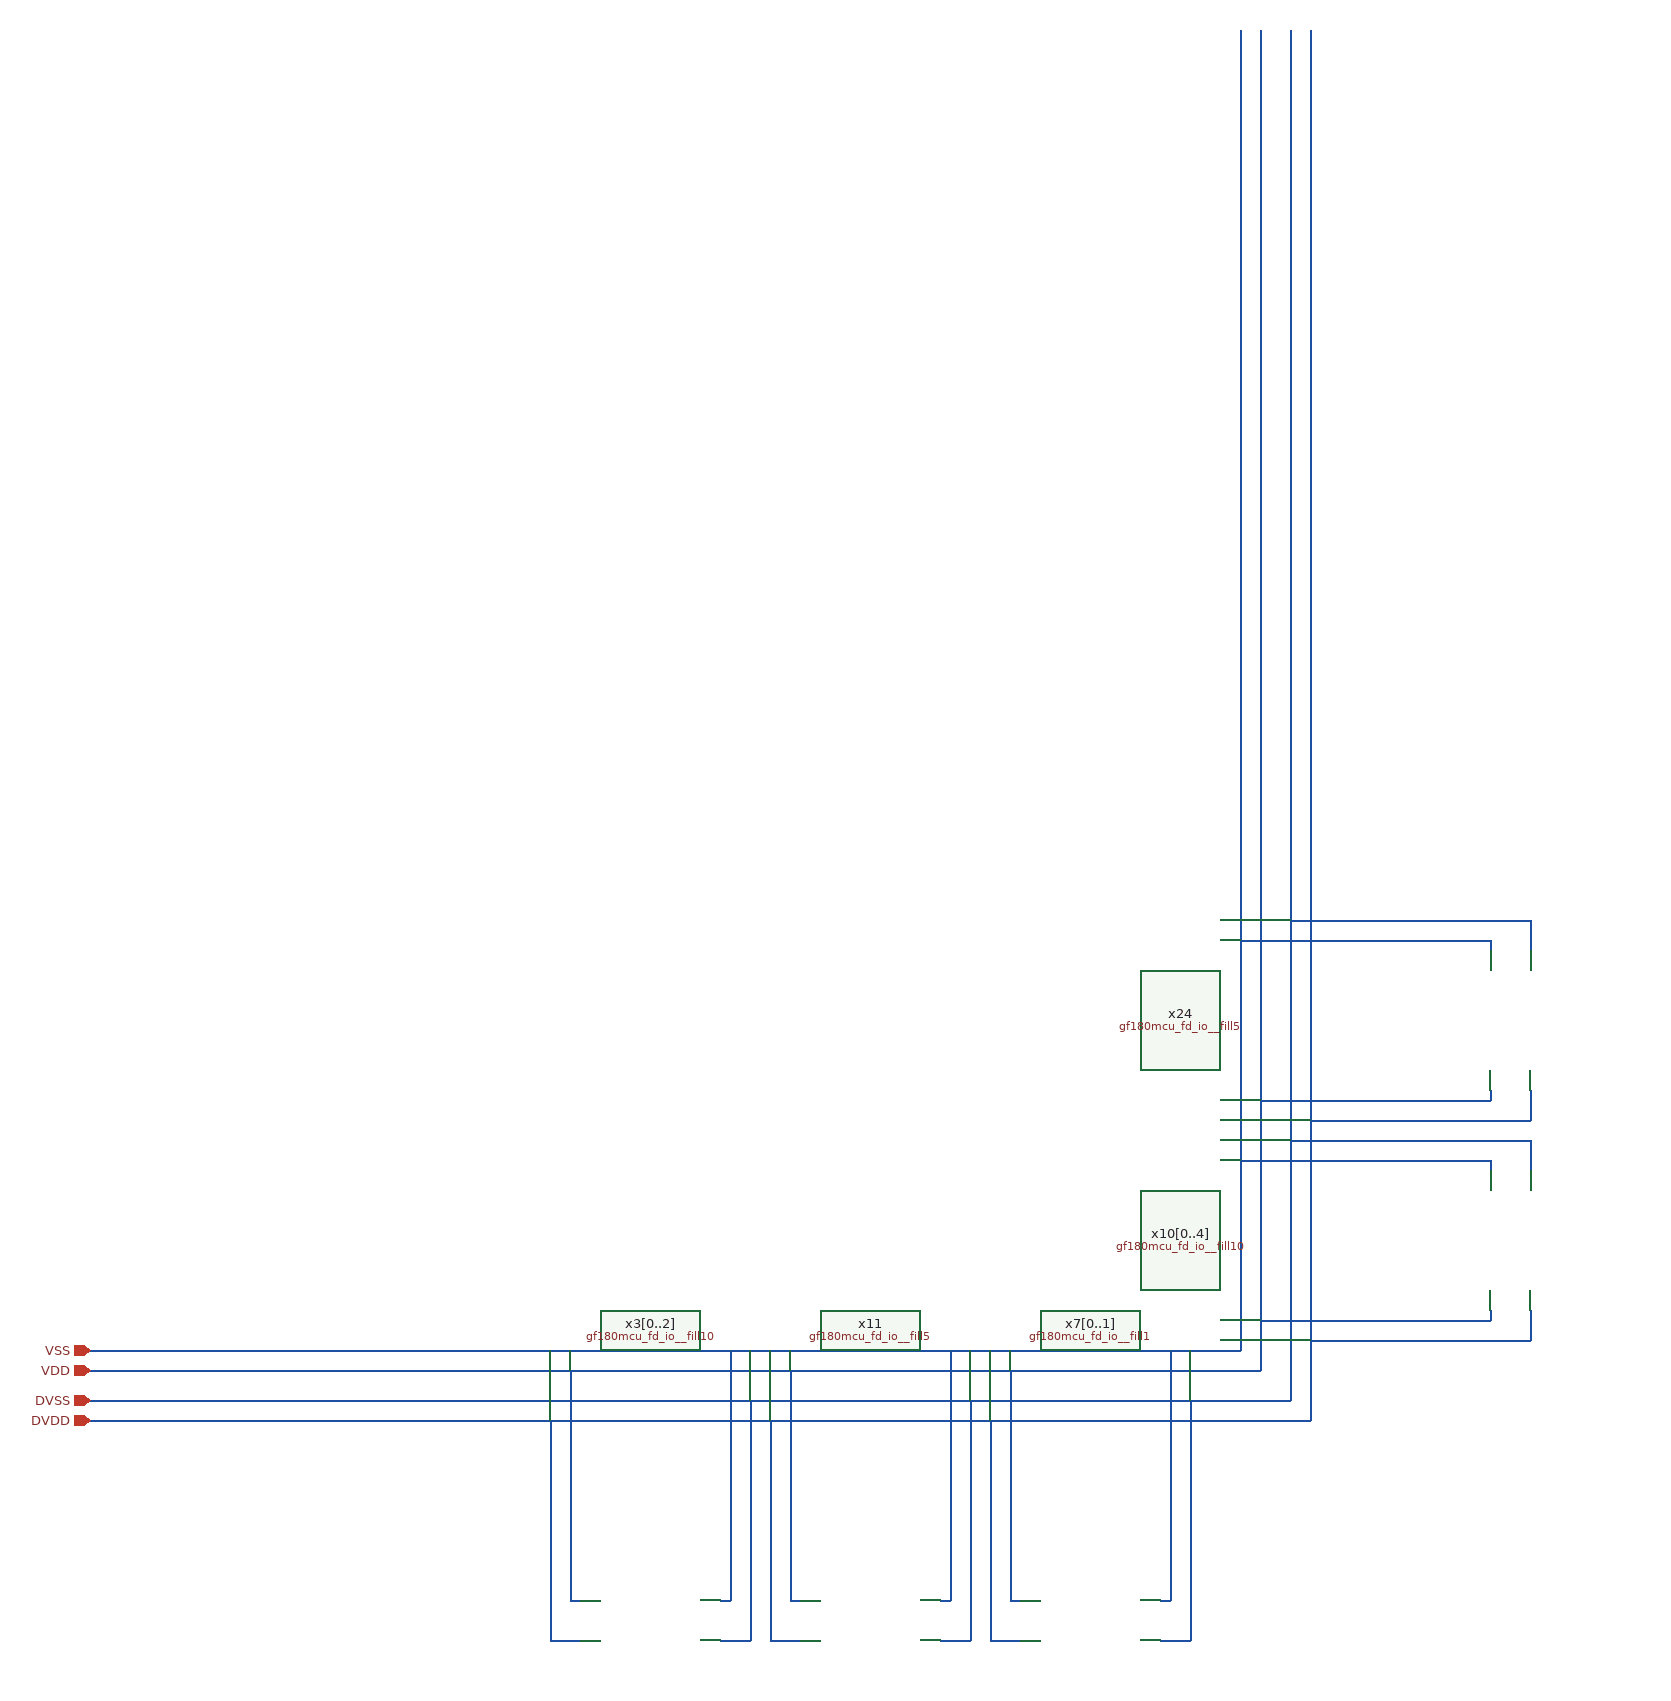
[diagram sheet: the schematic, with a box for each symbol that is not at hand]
v {xschem version=3.4.8RC file_version=1.3}
G {}
K {}
V {}
S {}
F {}
E {}
N 1210 220 1230 220 {lab=DVDD}
N 1200 0 1200 220 {lab=DVDD}
N 1220 180 1230 180 {lab=VDD}
N 1200 220 1210 220 {lab=DVDD}
N 1220 -50 1220 180 {lab=VDD}
N 1370 220 1400 220 {lab=DVSS}
N 1400 -20 1400 220 {lab=DVSS}
N 1370 180 1380 180 {lab=VSS}
N 1380 -70 1380 180 {lab=VSS}
N 740 0 1210 0 {lab=DVDD}
N 1210 0 1830 0 {lab=DVDD}
N 740 -20 1830 -20 {lab=DVSS}
N 740 -50 1860 -50 {lab=VDD}
N 740 -70 1860 -70 {lab=VSS}
N 1430 220 1450 220 {lab=DVDD}
N 1420 0 1420 220 {lab=DVDD}
N 1440 180 1450 180 {lab=VDD}
N 1420 220 1430 220 {lab=DVDD}
N 1440 -50 1440 180 {lab=VDD}
N 1590 220 1620 220 {lab=DVSS}
N 1620 -20 1620 220 {lab=DVSS}
N 1590 180 1600 180 {lab=VSS}
N 1600 -70 1600 180 {lab=VSS}
N 1650 220 1670 220 {lab=DVDD}
N 1640 0 1640 220 {lab=DVDD}
N 1660 180 1670 180 {lab=VDD}
N 1640 220 1650 220 {lab=DVDD}
N 1660 -50 1660 180 {lab=VDD}
N 1810 220 1840 220 {lab=DVSS}
N 1840 -20 1840 220 {lab=DVSS}
N 1810 180 1820 180 {lab=VSS}
N 1820 -70 1820 180 {lab=VSS}
N 1830 -20 1870 -20 {lab=DVSS}
N 1830 -0 1870 -0 {lab=DVDD}
N 1860 -50 1870 -50 {lab=VDD}
N 1860 -70 1870 -70 {lab=VSS}
N 1890 -1390 1890 -70 {lab=VSS}
N 1910 -1390 1910 -70 {lab=VDD}
N 1940 -1390 1940 -70 {lab=DVSS}
N 1960 -1390 1960 -70 {lab=DVDD}
N 1880 -70 1890 -70 {lab=VSS}
N 1880 -50 1910 -50 {lab=VDD}
N 1910 -70 1910 -50 {lab=VDD}
N 1880 -20 1940 -20 {lab=DVSS}
N 1940 -70 1940 -20 {lab=DVSS}
N 1880 0 1960 0 {lab=DVDD}
N 1960 -70 1960 0 {lab=DVDD}
N 2180 -110 2180 -90 {lab=DVDD}
N 1960 -80 2180 -80 {lab=DVDD}
N 2140 -110 2140 -100 {lab=VDD}
N 2180 -90 2180 -80 {lab=DVDD}
N 1910 -100 2140 -100 {lab=VDD}
N 2180 -280 2180 -250 {lab=DVSS}
N 1940 -280 2180 -280 {lab=DVSS}
N 2140 -260 2140 -250 {lab=VSS}
N 1890 -260 2140 -260 {lab=VSS}
N 1870 -70 1880 -70 {lab=VSS}
N 1870 -50 1880 -50 {lab=VDD}
N 1870 -20 1880 -20 {lab=DVSS}
N 1870 0 1880 0 {lab=DVDD}
N 2140 -330 2140 -320 {lab=VDD}
N 1910 -320 2140 -320 {lab=VDD}
N 2180 -500 2180 -470 {lab=DVSS}
N 1940 -500 2180 -500 {lab=DVSS}
N 2140 -480 2140 -470 {lab=VSS}
N 1890 -480 2140 -480 {lab=VSS}
N 2180 -330 2180 -310 {lab=DVDD}
N 1960 -300 2180 -300 {lab=DVDD}
N 2180 -310 2180 -300 {lab=DVDD}
C {/foss/pdks/gf180mcuD/libs.ref/gf180mcu_fd_io/xschem/gf180mcu_fd_io__fill10.sym} 1300 210 3 0 {name=x3[0..2]}
C {/foss/pdks/gf180mcuD/libs.ref/gf180mcu_fd_io/xschem/gf180mcu_fd_io__fill5.sym} 1520 210 3 0 {name=x11}
C {iopin.sym} 740 -70 2 0 {name=p1 lab=VSS}
C {iopin.sym} 740 -50 2 0 {name=p2 lab=VDD}
C {iopin.sym} 740 -20 2 0 {name=p3 lab=DVSS}
C {iopin.sym} 740 0 2 0 {name=p4 lab=DVDD}
C {/foss/pdks/gf180mcuD/libs.ref/gf180mcu_fd_io/xschem/gf180mcu_fd_io__fill1.sym} 1740 210 3 0 {name=x7[0..1]}
C {/foss/pdks/gf180mcuD/libs.ref/gf180mcu_fd_io/xschem/gf180mcu_fd_io__fill10.sym} 2170 -180 2 0 {name=x10[0..4]}
C {/foss/pdks/gf180mcuD/libs.ref/gf180mcu_fd_io/xschem/gf180mcu_fd_io__fill5.sym} 2170 -400 2 0 {name=x24}
